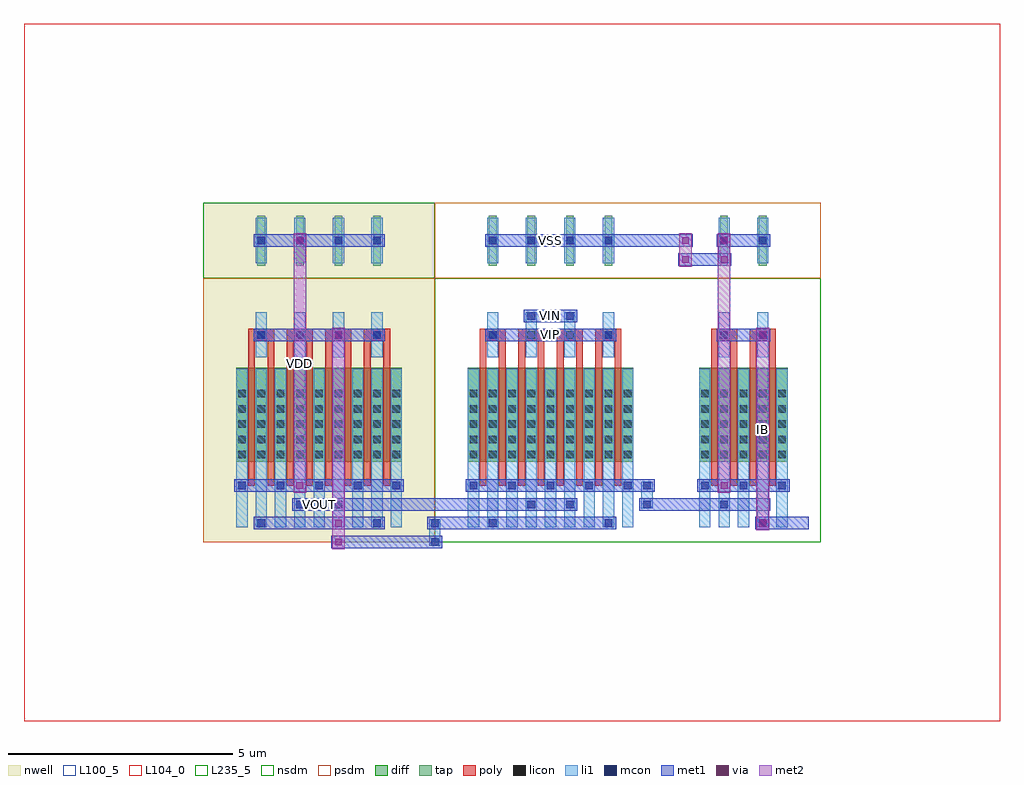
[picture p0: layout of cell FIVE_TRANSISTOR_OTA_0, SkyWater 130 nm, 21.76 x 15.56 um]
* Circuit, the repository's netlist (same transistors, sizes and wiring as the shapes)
* NGSPICE file created from FIVE_TRANSISTOR_OTA_0.ext - technology: sky130A

.subckt SCM_PMOS_9165244_X2_Y1_1772456889 a_200_252# a_402_357# w_0_0#
X0 a_200_252# a_200_252# w_0_0# w_0_0# sky130_fd_pr__pfet_01v8 ad=0.294 pd=2.38 as=0.5565 ps=4.73 w=2.1 l=0.15 M=4
X1 w_0_0# a_200_252# a_402_357# w_0_0# sky130_fd_pr__pfet_01v8 ad=0.294 pd=2.38 as=0.294 ps=2.38 w=2.1 l=0.15 M=4
.ends

.subckt SCM_NMOS_4295876_X1_Y1_1772456888 a_200_252# a_402_357# a_147_357#
X0 a_200_252# a_200_252# a_147_357# a_147_357# sky130_fd_pr__nfet_01v8 ad=0.294 pd=2.38 as=0.5565 ps=4.73 w=2.1 l=0.15 M=2
X1 a_402_357# a_200_252# a_147_357# a_147_357# sky130_fd_pr__nfet_01v8 ad=0.294 pd=2.38 as=0.294 ps=2.38 w=2.1 l=0.15 M=2
.ends

.subckt DP_NMOS_B_4373767_X2_Y1_1772456887 a_372_252# a_230_357# a_200_252# a_402_357#
+ a_147_357# a_241_1232#
X0 a_402_357# a_372_252# a_147_357# a_241_1232# sky130_fd_pr__nfet_01v8 ad=0.294 pd=2.38 as=0.294 ps=2.38 w=2.1 l=0.15 M=4
X1 a_230_357# a_200_252# a_147_357# a_241_1232# sky130_fd_pr__nfet_01v8 ad=0.294 pd=2.38 as=0.5565 ps=4.73 w=2.1 l=0.15 M=4
.ends

.subckt FIVE_TRANSISTOR_OTA_0 IB VSS VOUT VDD VIP VIN
XSCM_PMOS_9165244_X2_Y1_1772456889_0 li_1007_n17# VOUT VDD SCM_PMOS_9165244_X2_Y1_1772456889
XSCM_NMOS_4295876_X1_Y1_1772456888_0 IB li_1953_151# VSS SCM_NMOS_4295876_X1_Y1_1772456888
XDP_NMOS_B_4373767_X2_Y1_1772456887_0 VIN li_1007_n17# VIP VOUT li_1953_151# VSS DP_NMOS_B_4373767_X2_Y1_1772456887
.ends

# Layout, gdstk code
from math import pi, radians
import gdstk
lib = gdstk.Library(unit=1e-6, precision=1e-09)
def R(c, l, rs):  # rectangles x0, y0, x1, y1
    for r in rs: c.add(gdstk.rectangle(r[:2], r[2:], *l))
def A(c, l, x, y, w, h, nx, ny, dx, dy):  # array of equal rectangles
    R(c, l, [(x+i*dx, y+j*dy, x+i*dx+w, y+j*dy+h) for i in range(nx) for j in range(ny)])
def P(c, l, *ps):  # polygons
    for p in ps: c.add(gdstk.Polygon(p, *l))
nwell = (64, 20)
diff = (65, 20)
tap = (65, 44)
poly = (66, 20)
licon = (66, 44)
li1 = (67, 20)
mcon = (67, 44)
met1 = (68, 20)
via = (68, 44)
met2 = (69, 20)
nsdm = (93, 44)
psdm = (94, 20)
L100_5 = (100, 5)
L104_0 = (104, 0)
L235_5 = (235, 5)

scm_nmos_4295876_x1_y1_1 = lib.new_cell('SCM_NMOS_4295876_X1_Y1_1772456888')
R(scm_nmos_4295876_x1_y1_1, diff, [(0.735,1.785,2.705,3.885)])
R(scm_nmos_4295876_x1_y1_1, tap, [(1.205,6.16,1.375,7.28), (2.065,6.16,2.235,7.28)])
A(scm_nmos_4295876_x1_y1_1, poly, 1, 1.26, 0.15, 3.36, 4, 1, 0.43, 0)
R(scm_nmos_4295876_x1_y1_1, poly, [(1,4.485,1.58,4.755), (1.86,4.485,2.44,4.755)])
A(scm_nmos_4295876_x1_y1_1, licon, 0.775, 1.865, 0.17, 0.17, 3, 5, 0.43, 0.34)
A(scm_nmos_4295876_x1_y1_1, licon, 1.635, 1.865, 0.17, 0.17, 3, 5, 0.43, 0.34)
R(scm_nmos_4295876_x1_y1_1, licon, [(1.205,4.535,1.375,4.705), (2.065,4.535,2.235,4.705), (1.205,6.635,1.375,6.805), (2.065,6.635,2.235,6.805)])
A(scm_nmos_4295876_x1_y1_1, li1, 0.735, 0.335, 0.25, 3.53, 5, 1, 0.43, 0)
R(scm_nmos_4295876_x1_y1_1, li1, [(1.165,4.115,1.415,5.125), (2.025,4.115,2.275,5.125), (1.165,6.215,1.415,7.225), (2.025,6.215,2.275,7.225)])
A(scm_nmos_4295876_x1_y1_1, mcon, 0.775, 1.175, 0.17, 0.17, 3, 1, 0.86, 0)
R(scm_nmos_4295876_x1_y1_1, mcon, [(1.205,0.335,1.375,0.505), (2.065,0.755,2.235,0.925), (1.205,4.535,1.375,4.705), (2.065,4.535,2.235,4.705), (1.205,6.635,1.375,6.805), (2.065,6.635,2.235,6.805)])
R(scm_nmos_4295876_x1_y1_1, met1, [(0.26,0.28,1.46,0.56), (1.12,0.7,2.32,0.98), (0.69,1.12,2.75,1.4), (1.12,4.48,2.32,4.76), (1.12,6.58,2.32,6.86)])
R(scm_nmos_4295876_x1_y1_1, via, [(1.215,0.345,1.365,0.495), (2.075,1.185,2.225,1.335), (1.215,4.545,1.365,4.695), (2.075,6.645,2.225,6.795)])
R(scm_nmos_4295876_x1_y1_1, met2, [(1.15,0.26,1.43,4.78), (2.01,1.1,2.29,6.88)])
R(scm_nmos_4295876_x1_y1_1, nsdm, [(0,0,3.44,5.88)])
R(scm_nmos_4295876_x1_y1_1, psdm, [(0,5.88,3.44,7.56)])
R(scm_nmos_4295876_x1_y1_1, L100_5, [(0,0,3.44,7.56)])

scm_pmos_9165244_x2_y1_1 = lib.new_cell('SCM_PMOS_9165244_X2_Y1_1772456889')
R(scm_pmos_9165244_x2_y1_1, nwell, [(0,0,5.16,7.56)])
R(scm_pmos_9165244_x2_y1_1, diff, [(0.735,1.785,4.425,3.885)])
A(scm_pmos_9165244_x2_y1_1, tap, 1.205, 6.16, 0.17, 1.12, 4, 1, 0.86, 0)
A(scm_pmos_9165244_x2_y1_1, poly, 1, 1.26, 0.15, 3.36, 8, 1, 0.43, 0)
A(scm_pmos_9165244_x2_y1_1, poly, 1, 4.485, 0.58, 0.27, 4, 1, 0.86, 0)
A(scm_pmos_9165244_x2_y1_1, licon, 0.775, 1.865, 0.17, 0.17, 3, 5, 0.43, 0.34)
A(scm_pmos_9165244_x2_y1_1, licon, 1.635, 1.865, 0.17, 0.17, 3, 5, 0.43, 0.34)
A(scm_pmos_9165244_x2_y1_1, licon, 2.495, 1.865, 0.17, 0.17, 3, 5, 0.43, 0.34)
A(scm_pmos_9165244_x2_y1_1, licon, 3.355, 1.865, 0.17, 0.17, 3, 5, 0.43, 0.34)
A(scm_pmos_9165244_x2_y1_1, licon, 1.205, 4.535, 0.17, 0.17, 4, 2, 0.86, 2.1)
A(scm_pmos_9165244_x2_y1_1, li1, 0.735, 0.335, 0.25, 3.53, 9, 1, 0.43, 0)
A(scm_pmos_9165244_x2_y1_1, li1, 1.165, 4.115, 0.25, 1.01, 4, 2, 0.86, 2.1)
A(scm_pmos_9165244_x2_y1_1, mcon, 0.775, 1.175, 0.17, 0.17, 5, 1, 0.86, 0)
A(scm_pmos_9165244_x2_y1_1, mcon, 1.205, 4.535, 0.17, 0.17, 4, 2, 0.86, 2.1)
R(scm_pmos_9165244_x2_y1_1, mcon, [(1.205,0.335,1.375,0.505), (3.785,0.335,3.955,0.505), (2.065,0.755,2.235,0.925), (2.925,0.755,3.095,0.925)])
R(scm_pmos_9165244_x2_y1_1, met1, [(1.12,0.28,4.04,0.56), (1.98,0.7,3.18,0.98), (0.69,1.12,4.47,1.4), (1.12,4.48,4.04,4.76), (1.12,6.58,4.04,6.86)])
R(scm_pmos_9165244_x2_y1_1, via, [(2.075,0.345,2.225,0.495), (2.935,1.185,3.085,1.335), (2.075,4.545,2.225,4.695), (2.935,6.645,3.085,6.795)])
R(scm_pmos_9165244_x2_y1_1, met2, [(2.01,0.26,2.29,4.78), (2.87,1.1,3.15,6.88)])
R(scm_pmos_9165244_x2_y1_1, nsdm, [(0,5.88,5.16,7.56)])
R(scm_pmos_9165244_x2_y1_1, psdm, [(0,0,5.16,5.88)])
R(scm_pmos_9165244_x2_y1_1, L100_5, [(0,0,5.16,7.56)])

dp_nmos_b_4373767_x2_y1_ = lib.new_cell('DP_NMOS_B_4373767_X2_Y1_1772456887')
R(dp_nmos_b_4373767_x2_y1_, diff, [(0.735,1.785,4.425,3.885)])
A(dp_nmos_b_4373767_x2_y1_, tap, 1.205, 6.16, 0.17, 1.12, 4, 1, 0.86, 0)
A(dp_nmos_b_4373767_x2_y1_, poly, 1, 1.26, 0.15, 3.36, 8, 1, 0.43, 0)
A(dp_nmos_b_4373767_x2_y1_, poly, 1, 4.485, 0.58, 0.27, 4, 1, 0.86, 0)
A(dp_nmos_b_4373767_x2_y1_, licon, 0.775, 1.865, 0.17, 0.17, 3, 5, 0.43, 0.34)
A(dp_nmos_b_4373767_x2_y1_, licon, 1.635, 1.865, 0.17, 0.17, 3, 5, 0.43, 0.34)
A(dp_nmos_b_4373767_x2_y1_, licon, 2.495, 1.865, 0.17, 0.17, 3, 5, 0.43, 0.34)
A(dp_nmos_b_4373767_x2_y1_, licon, 3.355, 1.865, 0.17, 0.17, 3, 5, 0.43, 0.34)
A(dp_nmos_b_4373767_x2_y1_, licon, 1.205, 4.535, 0.17, 0.17, 4, 2, 0.86, 2.1)
A(dp_nmos_b_4373767_x2_y1_, li1, 0.735, 0.335, 0.25, 3.53, 9, 1, 0.43, 0)
A(dp_nmos_b_4373767_x2_y1_, li1, 1.165, 4.115, 0.25, 1.01, 4, 2, 0.86, 2.1)
A(dp_nmos_b_4373767_x2_y1_, mcon, 0.775, 1.175, 0.17, 0.17, 5, 1, 0.86, 0)
A(dp_nmos_b_4373767_x2_y1_, mcon, 1.205, 6.635, 0.17, 0.17, 4, 1, 0.86, 0)
R(dp_nmos_b_4373767_x2_y1_, mcon, [(1.205,0.335,1.375,0.505), (3.785,0.335,3.955,0.505), (2.065,0.755,2.235,0.925), (2.925,0.755,3.095,0.925), (1.205,4.535,1.375,4.705), (3.785,4.535,3.955,4.705), (2.065,4.955,2.235,5.125), (2.925,4.955,3.095,5.125)])
R(dp_nmos_b_4373767_x2_y1_, met1, [(1.12,0.28,4.04,0.56), (1.98,0.7,3.18,0.98), (0.69,1.12,4.47,1.4), (1.12,4.48,4.04,4.76), (1.98,4.9,3.18,5.18), (1.12,6.58,4.04,6.86)])
R(dp_nmos_b_4373767_x2_y1_, nsdm, [(0,0,5.16,5.88)])
R(dp_nmos_b_4373767_x2_y1_, psdm, [(0,5.88,5.16,7.56)])
R(dp_nmos_b_4373767_x2_y1_, L100_5, [(0,0,5.16,7.56)])

five_transistor_ota_0 = lib.new_cell('FIVE_TRANSISTOR_OTA_0')
R(five_transistor_ota_0, li1, [(5.035,-0.085,5.285,0.085), (5.035,-0.085,5.285,0.085), (5.035,0,5.285,0.42), (5.035,0.335,5.285,0.505), (5.035,0.335,5.285,0.505), (9.765,0.755,10.015,0.925), (9.765,0.755,10.015,0.925), (9.765,0.84,10.015,1.26), (9.765,1.175,10.015,1.345), (9.765,1.175,10.015,1.345)])
R(five_transistor_ota_0, mcon, [(5.075,-0.085,5.245,0.085), (5.075,-0.085,5.245,0.085), (5.075,0.335,5.245,0.505), (5.075,0.335,5.245,0.505), (9.805,0.755,9.975,0.925), (9.805,0.755,9.975,0.925), (9.805,1.175,9.975,1.345), (9.805,1.175,9.975,1.345)])
R(five_transistor_ota_0, met1, [(2.85,-0.14,3.17,0.14), (2.85,-0.14,3.17,0.14), (3.01,-0.14,5.16,0.14), (4.99,-0.14,5.33,0.14), (4.99,-0.14,5.33,0.14), (4.99,0.28,5.33,0.56), (4.99,0.28,5.33,0.56), (5.16,0.28,6.45,0.56), (3.01,0.7,7.31,0.98), (9.72,0.7,10.06,0.98), (9.72,0.7,10.06,0.98), (9.89,0.7,11.61,0.98), (9.46,1.12,9.89,1.4), (9.72,1.12,10.06,1.4), (9.72,1.12,10.06,1.4), (10.59,6.16,10.91,6.44), (10.59,6.16,10.91,6.44), (10.75,6.16,11.61,6.44), (11.45,6.16,11.77,6.44), (11.45,6.16,11.77,6.44), (9.03,6.58,10.75,6.86), (10.59,6.58,10.91,6.86), (10.59,6.58,10.91,6.86)])
P(five_transistor_ota_0, met1, [(0,0),(0,0),(0,0),(0,0)],
  [(0,0),(0,0),(0,0),(0,0)],
  [(0,0),(0,0),(0,0),(0,0)],
  [(0,0),(0,0),(0,0),(0,0)],
  [(0,0),(0,0),(0,0),(0,0)],
  [(0,0),(0,0),(0,0),(0,0)],
  [(0,0),(0,0),(0,0),(0,0)],
  [(0,0),(0,0),(0,0),(0,0)],
  [(0,0),(0,0),(0,0),(0,0)],
  [(0,0),(0,0),(0,0),(0,0)],
  [(0,0),(0,0),(0,0),(0,0)],
  [(0,0),(0,0),(0,0),(0,0)])
R(five_transistor_ota_0, via, [(2.935,-0.075,3.085,0.075), (2.935,-0.075,3.085,0.075), (10.675,6.225,10.825,6.375), (10.675,6.225,10.825,6.375), (11.535,6.225,11.685,6.375), (11.535,6.225,11.685,6.375), (10.675,6.645,10.825,6.795), (10.675,6.645,10.825,6.795)])
R(five_transistor_ota_0, met2, [(2.87,-0.16,3.15,0.16), (2.87,-0.16,3.15,0.16), (2.87,0,3.15,0.42), (10.61,6.14,10.89,6.46), (10.61,6.14,10.89,6.46), (11.47,6.14,11.75,6.46), (11.47,6.14,11.75,6.46), (10.61,6.3,10.89,6.72), (10.61,6.56,10.89,6.88), (10.61,6.56,10.89,6.88)])
P(five_transistor_ota_0, met2, [(0,0),(0,0),(0,0),(0,0)],
  [(0,0),(0,0),(0,0),(0,0)],
  [(0,0),(0,0),(0,0),(0,0)],
  [(0,0),(0,0),(0,0),(0,0)],
  [(0,0),(0,0),(0,0),(0,0)],
  [(0,0),(0,0),(0,0),(0,0)])
R(five_transistor_ota_0, L104_0, [(-4,-4,17.76,11.56)])
R(five_transistor_ota_0, L235_5, [(0,0,13.76,7.56)])
five_transistor_ota_0.add(gdstk.Reference(scm_nmos_4295876_x1_y1_1, (13.76,0), rotation=pi, x_reflection=True))
five_transistor_ota_0.add(gdstk.Reference(scm_pmos_9165244_x2_y1_1, (5.16,0), rotation=pi, x_reflection=True))
five_transistor_ota_0.add(gdstk.Reference(dp_nmos_b_4373767_x2_y1_, (5.16,0)))
five_transistor_ota_0.add(gdstk.Label('IB', (12.47,2.52), layer=69, texttype=5))
five_transistor_ota_0.add(gdstk.Label('VSS', (7.74,6.72), layer=68, texttype=5))
five_transistor_ota_0.add(gdstk.Label('VOUT', (2.58,0.84), layer=68, texttype=5))
five_transistor_ota_0.add(gdstk.Label('VDD', (2.15,3.99), layer=69, texttype=5))
five_transistor_ota_0.add(gdstk.Label('VIP', (7.74,4.62), layer=68, texttype=5))
five_transistor_ota_0.add(gdstk.Label('VIN', (7.74,5.04), layer=68, texttype=5))

lib.write_gds('FIVE_TRANSISTOR_OTA_0.gds')
